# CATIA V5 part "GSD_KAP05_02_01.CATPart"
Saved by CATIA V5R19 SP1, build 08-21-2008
Part number: GSD_KAP05_02_01
Definition: Beispielmodell: Punkte erzeugen
Description: CATIA V5 Flächenmodellierung  Copyright (c) 2009 Maik Hertha IT Consultants
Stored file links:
  \GSD_BUCH_UEBUNG\GSD_KAP05_02_01.CATPart

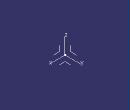
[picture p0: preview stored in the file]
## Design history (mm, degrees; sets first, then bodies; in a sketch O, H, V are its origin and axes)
AxisSystem1: origin (0, 0, 0), X (1, 0, 0), Y (0, 1, 0), Z (0, 0, 1)
Body1 (main body)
